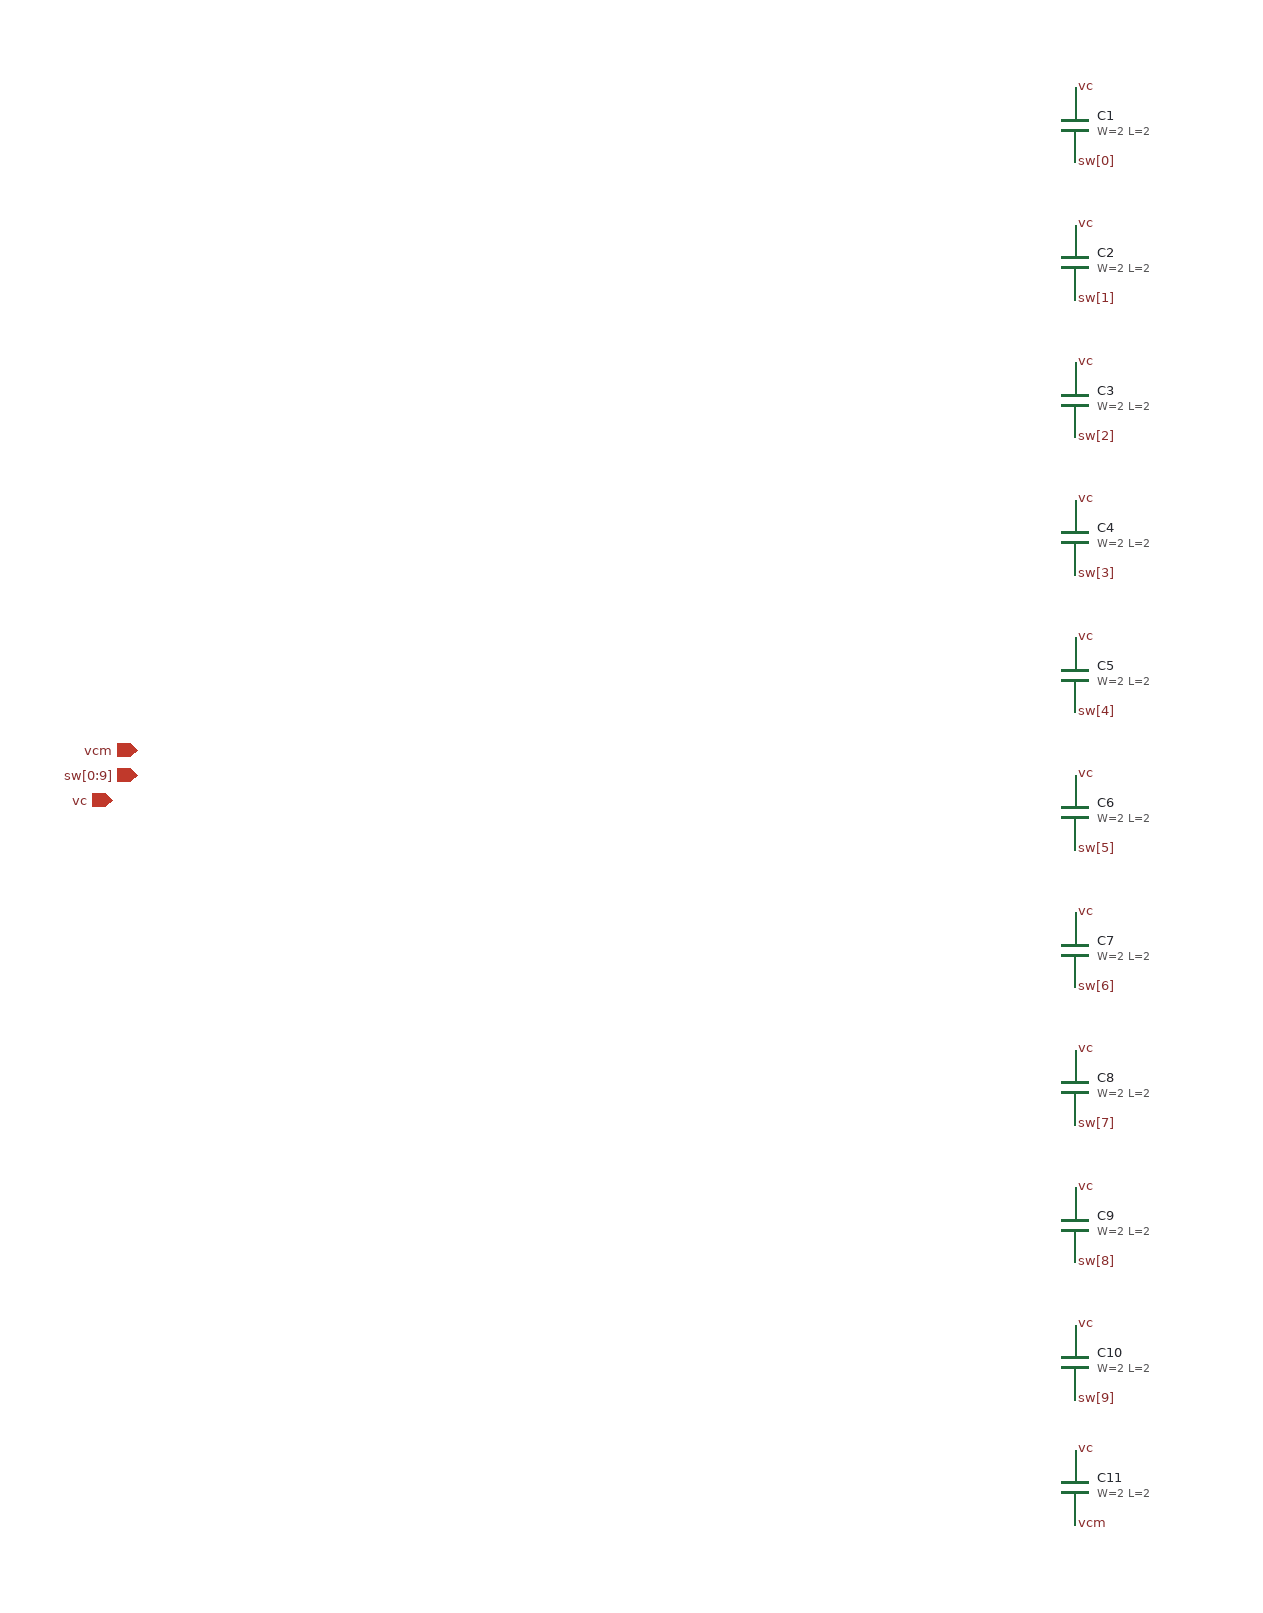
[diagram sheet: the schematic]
v {xschem version=3.4.5 file_version=1.2
}
G {}
K {}
V {}
S {}
E {}
C {devices/lab_wire.sym} 980 -80 2 0 {name=p1 sig_type=std_logic lab=vcm}
C {devices/lab_wire.sym} 980 -180 2 0 {name=p3 sig_type=std_logic lab=sw[9]}
C {devices/lab_wire.sym} 980 -290 2 0 {name=p5 sig_type=std_logic lab=sw[8]}
C {devices/lab_wire.sym} 980 -400 2 0 {name=p7 sig_type=std_logic lab=sw[7]}
C {devices/lab_wire.sym} 980 -510 2 0 {name=p9 sig_type=std_logic lab=sw[6]}
C {devices/lab_wire.sym} 980 -620 2 0 {name=p11 sig_type=std_logic lab=sw[5]}
C {devices/lab_wire.sym} 980 -730 2 0 {name=p13 sig_type=std_logic lab=sw[4]}
C {devices/lab_wire.sym} 980 -840 2 0 {name=p15 sig_type=std_logic lab=sw[3]}
C {devices/lab_wire.sym} 980 -950 2 0 {name=p17 sig_type=std_logic lab=sw[2]}
C {devices/lab_wire.sym} 980 -1060 2 0 {name=p19 sig_type=std_logic lab=sw[1]}
C {devices/lab_wire.sym} 980 -1170 2 0 {name=p21 sig_type=std_logic lab=sw[0]}
C {devices/ipin.sym} 230 -680 0 0 {name=p53 lab=sw[0:9]}
C {devices/ipin.sym} 230 -700 0 0 {name=p54 lab=vcm}
C {devices/iopin.sym} 210 -660 0 0 {name=p56 lab=vc

}
C {devices/lab_wire.sym} 980 -1230 0 1 {name=p30 sig_type=std_logic lab=vc}
C {sky130_fd_pr/cap_mim_m3_1.sym} 980 -1200 0 0 {name=C1 model=cap_mim_m3_1 W=2 L=2 MF=512 spiceprefix=X}
C {devices/lab_wire.sym} 980 -1120 0 1 {name=p31 sig_type=std_logic lab=vc}
C {sky130_fd_pr/cap_mim_m3_1.sym} 980 -1090 0 0 {name=C2 model=cap_mim_m3_1 W=2 L=2 MF=256 spiceprefix=X}
C {devices/lab_wire.sym} 980 -1010 0 1 {name=p32 sig_type=std_logic lab=vc}
C {sky130_fd_pr/cap_mim_m3_1.sym} 980 -980 0 0 {name=C3 model=cap_mim_m3_1 W=2 L=2 MF=128 spiceprefix=X}
C {devices/lab_wire.sym} 980 -900 0 1 {name=p33 sig_type=std_logic lab=vc}
C {sky130_fd_pr/cap_mim_m3_1.sym} 980 -870 0 0 {name=C4 model=cap_mim_m3_1 W=2 L=2 MF=64 spiceprefix=X}
C {devices/lab_wire.sym} 980 -790 0 1 {name=p34 sig_type=std_logic lab=vc}
C {sky130_fd_pr/cap_mim_m3_1.sym} 980 -760 0 0 {name=C5 model=cap_mim_m3_1 W=2 L=2 MF=32 spiceprefix=X}
C {devices/lab_wire.sym} 980 -680 0 1 {name=p35 sig_type=std_logic lab=vc}
C {sky130_fd_pr/cap_mim_m3_1.sym} 980 -650 0 0 {name=C6 model=cap_mim_m3_1 W=2 L=2 MF=16 spiceprefix=X}
C {devices/lab_wire.sym} 980 -570 0 1 {name=p36 sig_type=std_logic lab=vc}
C {sky130_fd_pr/cap_mim_m3_1.sym} 980 -540 0 0 {name=C7 model=cap_mim_m3_1 W=2 L=2 MF=8 spiceprefix=X}
C {devices/lab_wire.sym} 980 -460 0 1 {name=p37 sig_type=std_logic lab=vc}
C {sky130_fd_pr/cap_mim_m3_1.sym} 980 -430 0 0 {name=C8 model=cap_mim_m3_1 W=2 L=2 MF=4 spiceprefix=X}
C {devices/lab_wire.sym} 980 -350 0 1 {name=p38 sig_type=std_logic lab=vc}
C {sky130_fd_pr/cap_mim_m3_1.sym} 980 -320 0 0 {name=C9 model=cap_mim_m3_1 W=2 L=2 MF=2 spiceprefix=X}
C {devices/lab_wire.sym} 980 -240 0 1 {name=p39 sig_type=std_logic lab=vc}
C {sky130_fd_pr/cap_mim_m3_1.sym} 980 -210 0 0 {name=C10 model=cap_mim_m3_1 W=2 L=2 MF=1 spiceprefix=X}
C {sky130_fd_pr/cap_mim_m3_1.sym} 980 -110 0 0 {name=C11 model=cap_mim_m3_1 W=2 L=2 MF=1 spiceprefix=X}
C {devices/lab_wire.sym} 980 -140 0 1 {name=p71 sig_type=std_logic lab=vc}
